VERSION 5.7 ;
  NOWIREEXTENSIONATPIN ON ;
  DIVIDERCHAR "/" ;
  BUSBITCHARS "[]" ;
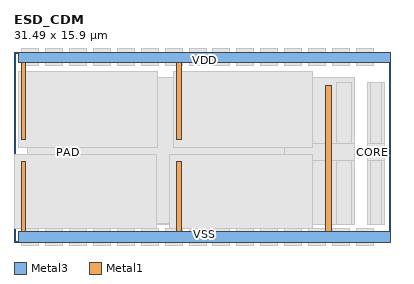
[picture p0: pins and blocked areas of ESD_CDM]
MACRO ESD_CDM
  CLASS BLOCK ;
  FOREIGN ESD_CDM ;
  ORIGIN 0.360 0.000 ;
  SIZE 31.490 BY 15.900 ;
  PIN PAD
    DIRECTION INPUT ;
    ANTENNADIFFAREA 200.000000 ;
    PORT
      LAYER Metal3 ;
      RECT 3.980 7.280 4.420 7.720 ;
    END
  END PAD
  PIN CORE
    DIRECTION OUTPUT ;
    PORT
      LAYER Metal3 ;
      RECT 29.740 7.280 30.180 7.720 ;
    END
  END CORE
  PIN VSS
    DIRECTION INOUT ;
    USE GROUND ;
    PORT
      LAYER Metal1 ;
        RECT 0.260 0.900 0.620 6.700 ;
        RECT 13.260 0.900 13.620 6.700 ;
        RECT 25.710 0.900 26.190 13.100 ;
        RECT 0.000 0.000 31.130 0.900 ;
      LAYER Metal3 ;
        RECT 0.000 0.000 31.130 0.900 ;
    END
  END VSS
  PIN VDD
    DIRECTION INOUT ;
    USE POWER ;
    PORT
      LAYER Metal1 ;
        RECT 0.000 15.000 31.130 15.900 ;
        RECT 0.260 8.600 0.620 15.000 ;
        RECT 13.260 8.600 13.620 15.000 ;
      LAYER Metal3 ;
        RECT 0.000 15.000 31.130 15.900 ;
    END
  END VDD
  OBS
      LAYER Via1 ;
        RECT 0.290 -0.260 1.710 1.160 ;
        RECT 2.290 -0.260 3.710 1.160 ;
        RECT 4.290 -0.260 5.710 1.160 ;
        RECT 6.290 -0.260 7.710 1.160 ;
        RECT 8.290 -0.260 9.710 1.160 ;
        RECT 10.290 -0.260 11.710 1.160 ;
        RECT 12.290 -0.260 13.710 1.160 ;
        RECT 14.290 -0.260 15.710 1.160 ;
        RECT 16.290 -0.260 17.710 1.160 ;
        RECT 18.290 -0.260 19.710 1.160 ;
        RECT 20.290 -0.260 21.710 1.160 ;
        RECT 22.290 -0.260 23.710 1.160 ;
        RECT 24.290 -0.260 25.710 1.160 ;
        RECT 26.290 -0.260 27.710 1.160 ;
        RECT 28.290 -0.260 29.710 1.160 ;
        RECT 29.250 1.470 30.670 13.330 ;
        RECT 0.810 1.470 28.110 13.790 ;
        RECT 0.290 14.740 1.710 16.160 ;
        RECT 2.290 14.740 3.710 16.160 ;
        RECT 4.290 14.740 5.710 16.160 ;
        RECT 6.290 14.740 7.710 16.160 ;
        RECT 8.290 14.740 9.710 16.160 ;
        RECT 10.290 14.740 11.710 16.160 ;
        RECT 12.290 14.740 13.710 16.160 ;
        RECT 14.290 14.740 15.710 16.160 ;
        RECT 16.290 14.740 17.710 16.160 ;
        RECT 18.290 14.740 19.710 16.160 ;
        RECT 20.290 14.740 21.710 16.160 ;
        RECT 22.290 14.740 23.710 16.160 ;
        RECT 24.290 14.740 25.710 16.160 ;
        RECT 26.290 14.740 27.710 16.160 ;
        RECT 28.290 14.740 29.710 16.160 ;
      LAYER Via2 ;
        RECT 0.290 -0.260 1.710 1.160 ;
        RECT 2.290 -0.260 3.710 1.160 ;
        RECT 4.290 -0.260 5.710 1.160 ;
        RECT 6.290 -0.260 7.710 1.160 ;
        RECT 8.290 -0.260 9.710 1.160 ;
        RECT 10.290 -0.260 11.710 1.160 ;
        RECT 12.290 -0.260 13.710 1.160 ;
        RECT 14.290 -0.260 15.710 1.160 ;
        RECT 16.290 -0.260 17.710 1.160 ;
        RECT 18.290 -0.260 19.710 1.160 ;
        RECT 20.290 -0.260 21.710 1.160 ;
        RECT 22.290 -0.260 23.710 1.160 ;
        RECT 24.290 -0.260 25.710 1.160 ;
        RECT 26.290 -0.260 27.710 1.160 ;
        RECT 28.290 -0.260 29.710 1.160 ;
        RECT 3.490 6.790 4.910 8.210 ;
        RECT 22.250 6.790 28.110 8.210 ;
        RECT 29.250 6.790 30.670 8.210 ;
        RECT 0.290 14.740 1.710 16.160 ;
        RECT 2.290 14.740 3.710 16.160 ;
        RECT 4.290 14.740 5.710 16.160 ;
        RECT 6.290 14.740 7.710 16.160 ;
        RECT 8.290 14.740 9.710 16.160 ;
        RECT 10.290 14.740 11.710 16.160 ;
        RECT 12.290 14.740 13.710 16.160 ;
        RECT 14.290 14.740 15.710 16.160 ;
        RECT 16.290 14.740 17.710 16.160 ;
        RECT 18.290 14.740 19.710 16.160 ;
        RECT 20.290 14.740 21.710 16.160 ;
        RECT 22.290 14.740 23.710 16.160 ;
        RECT 24.290 14.740 25.710 16.160 ;
        RECT 26.290 14.740 27.710 16.160 ;
        RECT 28.290 14.740 29.710 16.160 ;
      LAYER Metal1 ;
        RECT 26.640 1.470 27.850 13.330 ;
        RECT 29.510 1.470 30.410 13.330 ;
        RECT 0.810 1.510 24.190 13.790 ;
      LAYER Metal2 ;
        RECT 0.290 -0.260 1.710 1.160 ;
        RECT 2.290 -0.260 3.710 1.160 ;
        RECT 4.290 -0.260 5.710 1.160 ;
        RECT 6.290 -0.260 7.710 1.160 ;
        RECT 8.290 -0.260 9.710 1.160 ;
        RECT 10.290 -0.260 11.710 1.160 ;
        RECT 12.290 -0.260 13.710 1.160 ;
        RECT 14.290 -0.260 15.710 1.160 ;
        RECT 16.290 -0.260 17.710 1.160 ;
        RECT 18.290 -0.260 19.710 1.160 ;
        RECT 20.290 -0.260 21.710 1.160 ;
        RECT 22.290 -0.260 23.710 1.160 ;
        RECT 24.290 -0.260 25.710 1.160 ;
        RECT 26.290 -0.260 27.710 1.160 ;
        RECT 28.290 -0.260 29.710 1.160 ;
        RECT 3.490 6.790 4.910 8.210 ;
        RECT 22.250 6.790 28.110 8.210 ;
        RECT 29.250 6.790 30.670 8.210 ;
        RECT 0.290 14.740 1.710 16.160 ;
        RECT 2.290 14.740 3.710 16.160 ;
        RECT 4.290 14.740 5.710 16.160 ;
        RECT 6.290 14.740 7.710 16.160 ;
        RECT 8.290 14.740 9.710 16.160 ;
        RECT 10.290 14.740 11.710 16.160 ;
        RECT 12.290 14.740 13.710 16.160 ;
        RECT 14.290 14.740 15.710 16.160 ;
        RECT 16.290 14.740 17.710 16.160 ;
        RECT 18.290 14.740 19.710 16.160 ;
        RECT 20.290 14.740 21.710 16.160 ;
        RECT 22.290 14.740 23.710 16.160 ;
        RECT 24.290 14.740 25.710 16.160 ;
        RECT 26.290 14.740 27.710 16.160 ;
        RECT 28.290 14.740 29.710 16.160 ;
      LAYER Pwell ;
        RECT -0.360 1.100 11.600 7.300 ;
        RECT 12.640 1.100 24.600 7.300 ;
      LAYER Nwell ;
        RECT -0.020 7.950 11.650 14.250 ;
        RECT 12.980 7.950 24.650 14.250 ;
  END
END ESD_CDM
